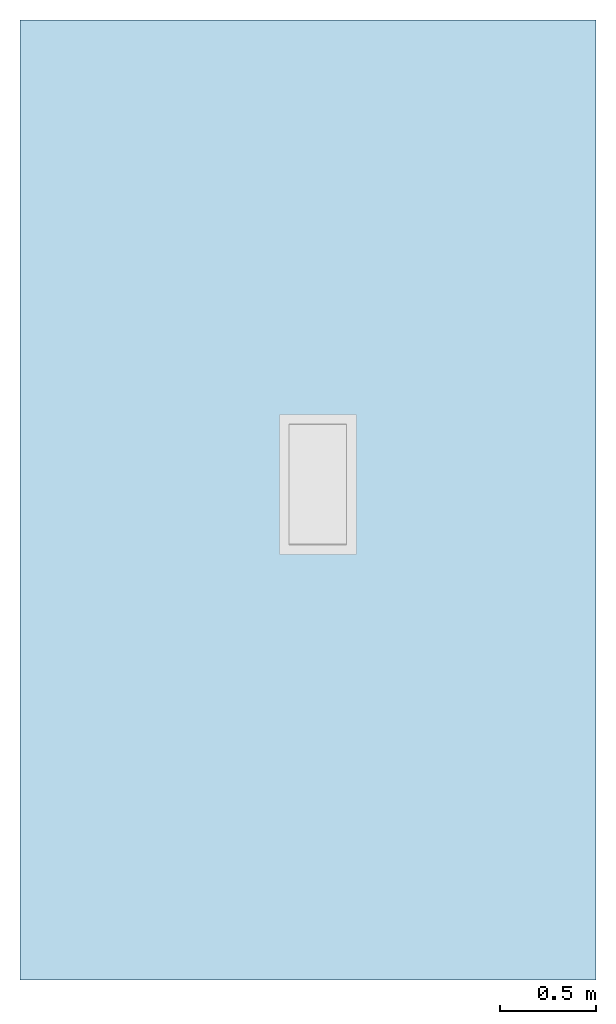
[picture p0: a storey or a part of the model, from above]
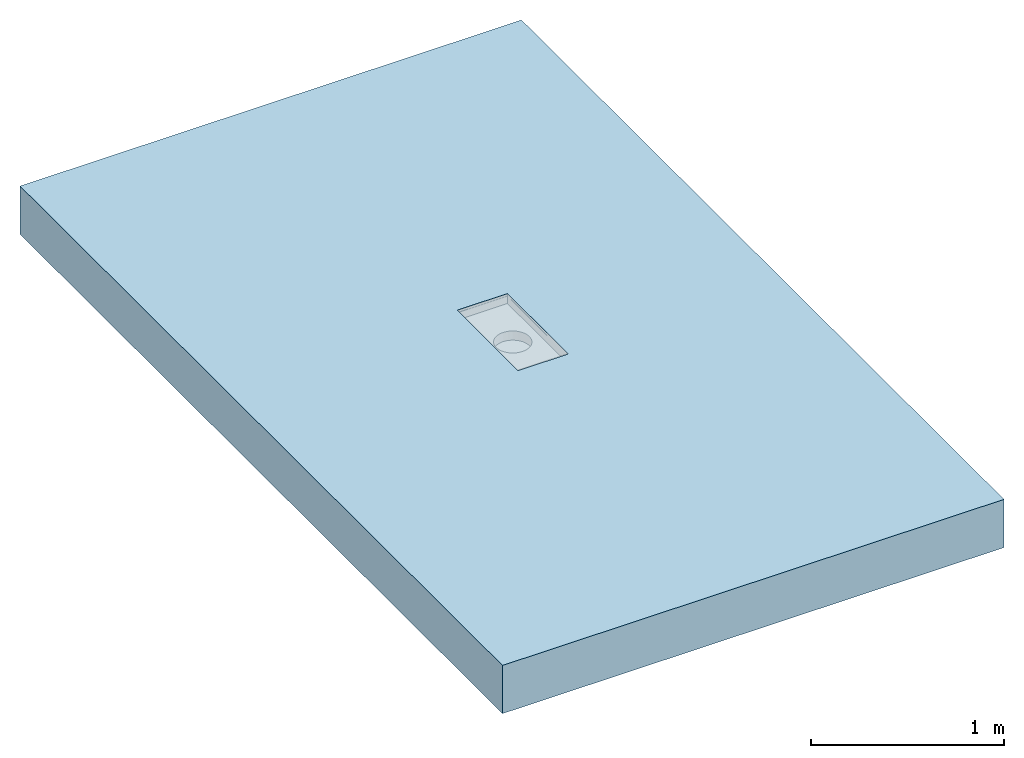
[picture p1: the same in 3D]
Properties of the parts of a building model (IFC2X3)

# File
Description: ViewDefinition [CoordinationView]
File name: Project Number
Time: 2016-11-22T09:35:19
Written by: The EXPRESS Data Manager Version 5.01.0100.02.64mod : 6 Jun 2012
Made in: 20130308_1515(x64) - Exporter 2014.0.2013.0308 - Default UI
Comment: STEP Physical File produced by: The EXPRESS Data Manager Version 5.01.0100.02.64mod : 6 Jun 2012 * Module: EDMstepFileFactory/EDMstandAlone * Creation date: Tue Nov 22 09:35:19 2016 * Host: IN-BLR-PC-0012 * Database: C:\Users\pakumar\AppData\Local\Temp\{2845CE25-2BB1-4A44-9AA8-B5BEA6DCF83F}\ifc * Database version: 5507 * Database creation date: Tue Nov 22 09:35:18 2016 * Schema: IFC2X3 * Model: DataRepository.ifc * Model creation date: Tue Nov 22 09:35:18 2016 * Header model: DataRepository.ifc_HeaderModel * Header model creation date: Tue Nov 22 09:35:18 2016 * EDMuser: sdai-user * EDMgroup: sdai-group * License ID and type: 5605 : Permanent license. Expiry date: * EDMstepFileFactory options: 020000

# IfcProject, Project Number
LongName: Project Name; Phase: Project Status

# IfcSite, Default
RefLatitude: 42, 21, 30, 344238; RefLongitude: -71, -3, -35, -194702; RefElevation: 0 mm

# IfcBuilding
Pset_BuildingCommon - NumberOfStoreys: 1
Other - Project Status: Project Status; Project Address: Enter address here; Project Name: Project Name; Project Issue Date: Issue Date; Client Name: Owner; Project Number: Project Number

# IfcBuildingStorey, Level 1
LongName: Level 1; Elevation: 0 mm
Constraints - Elevation Base: Project Base Point; Elevation: 0 mm
Graphics - Color: 0; Line Weight: 1; Symbol at End 1 Default: no; Line Pattern: Grid Line 1/2"; Symbol: Level Head - Circle: Level Head - Circle; Symbol at End 2 Default: yes
Identity Data - Structural: no; Name: Level 1; Building Story: yes
Dimensions - Computation Height: 0 mm

# IfcFlowTerminal: 416718 - Hygienic Extended Channel - with Gully 218 - 600mm LG - 300mm Wide, ACO Tray Channel - Hygienic - Extended - 300mm Wide:416718 - Hygienic Extended Channel - with Gully 218 - 600mm LG - 300mm Wide:337363
In: Level 1
Material: Stainless Steel AISI 304, Stainless Steel AISI 304 - Grating
Construction - Grating: yes; Detail - Outlet 200: yes; Detail - Outlet 142mm: no; 416864 - 268 x 298mm - Mesh Grating - L15 - Stainless Steel 1.4301: no; 416884 - 268 x 298mm - Mesh Grating - L15 - Stainless Steel 1.4301: no; 416866 - 268 x 499mm - Mesh Grating - L15 - Stainless Steel 1.4301: no; 416812 - 268 x 298mm - Ladder Grating - R50 - Stainless Steel 1.4301: no; 416886 - 268 x 499mm - Mesh Grating - L15 - Stainless Steel 1.4301: no; 416816 - 268 x 298mm - Ladder Grating - M125 - Stainless Steel 1.4301: no; 416946 - 268 x 299mm - Casted Grating - M125 - Stainless Steel 1.4301: yes; 416818 - 268 x 499mm - Ladder Grating - M125 - Stainless Steel 1.4301: no; 416945 - 268 x 499mm - Casted Grating - M125 - Stainless Steel 1.4301: no; 416814 - 268 x 499mm - Ladder Grating - R50 - Stainless Steel 1.4301: no
Phasing - Phase Created: New Construction
Mechanical - System Classification: Sanitary
Identity Data - Mark: 15; Watermarked By: www.acobd.com; Website: www.acobd.com; Cost: 0; Watermark1: This file is the property of ACO Technologies PLC.; Manufacturer: ACO Building Drainage; Watermark2: This file is water marked and users are prohibited to reproduce, adapt, distribute this information.; Watermarked With: BIM Manager Premium Suite.; E-mail Sales: abdcommercial@aco.co.uk; Address: ACO Business Centre, Caxton Road, Bedford, MK41 0LF; Telephone: +44 (0)1462 816666; Fax: +44 (0)1462 851490; E-mail Technical: abdtechnical@aco.co.uk
Constraints - Level: Level: Level 1
Pset_ManufacturerTypeInformation - Manufacturer: ACO Building Drainage
Other - Invert Depth Detail: 51.5 mm; 416614 - Hygienic Standard Channel - 300mm LG - 300mm Wide: no; 416617 - Hygienic Standard Channel - 1500mm LG - 300mm Wide: no; 416619 - Hygienic Standard Channel - 3000mm LG - 300mm Wide: no; 416615 - Hygienic Standard Channel - 600mm LG - 300mm Wide: yes; 416618 - Hygienic Standard Channel - 2000mm LG - 300mm Wide: no; 416616 - Hygienic Standard Channel - 1000mm LG - 300mm Wide: no; Flow: 0.155385 m3/s; Number mesh: 24; Spigot Outlets Channels: yes; 416620 - Hygienic Standard Channel - 4000mm LG - 300mm Wide: no
Dimensions - Spigot Distance: 300 mm; Grating Void Cut Length: 500 mm; Length Channel: -570 mm; Grating Height: 21 mm; Endplate Position: 600 mm; End Plate: 600 mm; Depth: 29 mm; Outside Outlet Rad: 100 mm; Number of gratings: 2; End Connection Plate End: -600 mm; Outlet: 200 mm; Floor Cut Void Height: 62.8 mm; Grating Length: 298 mm; x: -615 mm; Inside Outlet Rad: 98 mm; Invert Depth: 50 mm; End Connection Plate Start: -570 mm
General - Weight (Kg): 5.7; Product Range: ACO Hygiene First; Installation guidelines: http://issuu.com/acobuildingdrainage/docs/aco_hygiene_first_catalogue/17?e=0; Product Standard: EN 1253 / EN 1672 / EN ISO 14159; Product Type: Extended Kitchen Tray Channel; Outlet Diameter (mm): 200; Load Class: A15 - C250 (EN 1253); Foul air trap Recyclable: Fully recyclable; Channel Dimension: 300 x 630; Channel Recycled material content: 20 - 30 %; Foul air trap seal Colour: Black; Product Code: 416718; Maintenance guidelines: http://issuu.com/acobuildingdrainage/docs/aco_hygiene_first_catalogue/17?e=0; Foul air trap Recycled material content: 0%; Channel Material: Stainless steel 1.4301 (EN 10088); Channel Colour: passivated stainless steel surface ( matt grey); Price: POA - contact ACO; Product Description: ACO Hygiene First Extended Kitchen Tray Channel 300 x 630 / 200 Dia Outlet & Foul Air Trap; Channel Recyclable: Fully recyclable; Foul air trap seal Material: NBR
Model Properties - Grating Product Code 416866: N/A; Grating Product Code 416814: N/A; Grating Product Code 416864: Load Class L 15 (EN 1253) - Mesh Grate - Stainless steel 1.4301 (EN 10088) - 268 x 298 - 2kg; Grating Product Code 416818: N/A; Grating Product Code 416816: Load Class M 125 (EN 1253) - Ladder Grate - Stainless steel 1.4301 (EN 10088) - 268 x 298 - 4.1kg; Grating Product Code 416884: Load Class L 15 (EN 1253) - Mesh Grate - Stainless steel 1.4301 (EN 10088) - 268 x 298 - 2.1kg; Grating Product Code 416946: Load Class M 125 (EN 1253) - Cast Grate - Stainless steel 1.4301 (EN 10088) - 268 x 299 - 6.9kg; Grating Product Code 416945: N/A; Grating Product Code 416886: N/A; Grating Product Code 416812: Load Class R 50 (EN 1253) - Ladder Grate - Stainless steel 1.4301 (EN 10088) - 268 x 298 - 2.5kg

# IfcOpeningElement: Recess
In: Level 1
Dimensions - Thickness: 304.8 mm; Perimeter: 16000 mm; Volume: 160.97 ft3; Area: 161.459 ft2
Constraints - Level: Level: Level 1; Related to Mass: no; Room Bounding: yes; Height Offset From Level: 0 mm
Structural - Structural: no; Enable Analytical Model: no
Phasing - Phase Created: New Construction
Identity Data - Assembly Code: B1010; Assembly Description: Floor Construction
Analytical Properties - Roughness: 3; Absorptance: 0.7
Construction - Function: Interior; Default Thickness: 304.8 mm
Graphics - Coarse Scale Fill Color: 0

# IfcSlab: Floor:Generic - 12", Floor:Generic - 12":184145
In: Level 1
PredefinedType: FLOOR; Material: Default Floor 304.8 mm
Dimensions - Thickness: 304.8 mm; Perimeter: 16000 mm; Volume: 160.97 ft3; Area: 161.459 ft2
Constraints - Level: Level: Level 1; Related to Mass: no; Room Bounding: yes; Height Offset From Level: 0 mm
Structural - Structural: no; Enable Analytical Model: no
Phasing - Phase Created: New Construction
Pset_SlabCommon - Reference: Generic - 12"; IsExternal: no; LoadBearing: yes
Identity Data - Assembly Code: B1010; Assembly Description: Floor Construction
Analytical Properties - Roughness: 3; Absorptance: 0.7
Construction - Function: Interior; Default Thickness: 304.8 mm
Graphics - Coarse Scale Fill Color: 0
